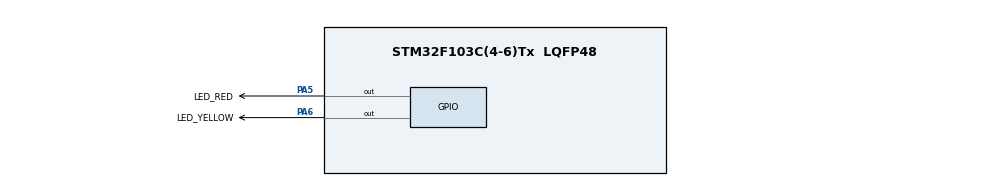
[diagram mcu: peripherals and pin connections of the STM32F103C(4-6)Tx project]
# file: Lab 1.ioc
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Mcu.Family=STM32F1
Mcu.Name=STM32F103C(4-6)Tx
Mcu.Package=LQFP48
NVIC.PriorityGroup=NVIC_PRIORITYGROUP_4
PA5.GPIO_Label=LED_RED
PA5.Signal=GPIO_Output
PA6.GPIO_Label=LED_YELLOW
PA6.Signal=GPIO_Output
ProjectManager.HeapSize=0x200
ProjectManager.StackSize=0x400
ProjectManager.TargetToolchain=STM32CubeIDE
RCC.APB1Freq_Value=8000000
RCC.APB2Freq_Value=8000000
VP_SYS_VS_ND.Mode=No_Debug
board=custom

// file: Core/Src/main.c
/* USER CODE BEGIN Header */
/**
 ******************************************************************************
 * @file           : main.c
 * @brief          : Main program body
 ******************************************************************************
 * @attention
 *
 * Copyright (c) 2025 STMicroelectronics.
 * All rights reserved.
 *
 * This software is licensed under terms that can be found in the LICENSE file
 * in the root directory of this software component.
 * If no LICENSE file comes with this software, it is provided AS-IS.
 *
 ******************************************************************************
 */
/* USER CODE END Header */
#include "main.h"

/* USER CODE BEGIN PV */

int LED_Pins[12] = {
    LED1_Pin, LED2_Pin, LED3_Pin, LED4_Pin,
    LED5_Pin, LED6_Pin, LED7_Pin, LED8_Pin,
    LED9_Pin, LED10_Pin, LED11_Pin, LED12_Pin
};

/* USER CODE END PV */

void SystemClock_Config(void);
static void MX_GPIO_Init(void);

/* USER CODE BEGIN 0 */

void setAllClock()
{
	for (int i = 0; i < 12; i++)
	{
		HAL_GPIO_WritePin(GPIOA, LED_Pins[i], GPIO_PIN_SET);
	}
}

void clearAllClock()
{
	for (int i = 0; i < 12; i++)
	{
		HAL_GPIO_WritePin(GPIOA, LED_Pins[i], GPIO_PIN_RESET);
	}
}

void setNumberOnClock(int num)
{
    HAL_GPIO_WritePin(GPIOA, LED_Pins[num], GPIO_PIN_SET);
}

void clearNumberOnClock(int num)
{
    HAL_GPIO_WritePin(GPIOA, LED_Pins[num], GPIO_PIN_RESET);
}

/* USER CODE END 0 */

int main(void)
{

  /* MCU Configuration--------------------------------------------------------*/

  /* Reset of all peripherals, Initializes the Flash interface and the Systick. */
  HAL_Init();

  /* Configure the system clock */
  SystemClock_Config();

  /* Initialize all configured peripherals */
  MX_GPIO_Init();

  /* Infinite loop */
  /* USER CODE BEGIN WHILE */

    int current_led = 0;
    setAllClock();
    HAL_Delay(250);
    while(1)
    {
    /* USER CODE END WHILE */

    /* USER CODE BEGIN 3 */
    	if(current_led < 12)
		{
			clearNumberOnClock(current_led);
			current_led++;
		}
    	else
    	{
    		setAllClock();
			current_led = 0;
		}

		HAL_Delay(250);
    }
  /* USER CODE END 3 */
}

void SystemClock_Config(void)
{
  RCC_OscInitTypeDef RCC_OscInitStruct = {0};
  RCC_ClkInitTypeDef RCC_ClkInitStruct = {0};

  /** Initializes the RCC Oscillators according to the specified parameters
  * in the RCC_OscInitTypeDef structure.
  */
  RCC_OscInitStruct.OscillatorType = RCC_OSCILLATORTYPE_HSI;
  RCC_OscInitStruct.HSIState = RCC_HSI_ON;
  RCC_OscInitStruct.HSICalibrationValue = RCC_HSICALIBRATION_DEFAULT;
  RCC_OscInitStruct.PLL.PLLState = RCC_PLL_NONE;
  if (HAL_RCC_OscConfig(&RCC_OscInitStruct) != HAL_OK)
  {
    Error_Handler();
  }

  /** Initializes the CPU, AHB and APB buses clocks
  */
  RCC_ClkInitStruct.ClockType = RCC_CLOCKTYPE_HCLK|RCC_CLOCKTYPE_SYSCLK
                              |RCC_CLOCKTYPE_PCLK1|RCC_CLOCKTYPE_PCLK2;
  RCC_ClkInitStruct.SYSCLKSource = RCC_SYSCLKSOURCE_HSI;
  RCC_ClkInitStruct.AHBCLKDivider = RCC_SYSCLK_DIV1;
  RCC_ClkInitStruct.APB1CLKDivider = RCC_HCLK_DIV1;
  RCC_ClkInitStruct.APB2CLKDivider = RCC_HCLK_DIV1;

  if (HAL_RCC_ClockConfig(&RCC_ClkInitStruct, FLASH_LATENCY_0) != HAL_OK)
  {
    Error_Handler();
  }
}

static void MX_GPIO_Init(void)
{
  GPIO_InitTypeDef GPIO_InitStruct = {0};

  /* GPIO Ports Clock Enable */
  __HAL_RCC_GPIOA_CLK_ENABLE();

  /*Configure GPIO pin Output Level */
  HAL_GPIO_WritePin(GPIOA, LED1_Pin|LED2_Pin|LED3_Pin|LED4_Pin
                          |LED5_Pin|LED6_Pin|LED7_Pin|LED8_Pin
                          |LED9_Pin|LED10_Pin|LED11_Pin|LED12_Pin, GPIO_PIN_RESET);

  /*Configure GPIO pins : LED1_Pin LED2_Pin LED3_Pin LED4_Pin
                           LED5_Pin LED6_Pin LED7_Pin LED8_Pin
                           LED9_Pin LED10_Pin LED11_Pin LED12_Pin */
  GPIO_InitStruct.Pin = LED1_Pin|LED2_Pin|LED3_Pin|LED4_Pin
                          |LED5_Pin|LED6_Pin|LED7_Pin|LED8_Pin
                          |LED9_Pin|LED10_Pin|LED11_Pin|LED12_Pin;
  GPIO_InitStruct.Mode = GPIO_MODE_OUTPUT_PP;
  GPIO_InitStruct.Pull = GPIO_NOPULL;
  GPIO_InitStruct.Speed = GPIO_SPEED_FREQ_LOW;
  HAL_GPIO_Init(GPIOA, &GPIO_InitStruct);

}

void Error_Handler(void)
{
  /* USER CODE BEGIN Error_Handler_Debug */
    /* User can add his own implementation to report the HAL error return state
     */
    __disable_irq();
    while(1)
    {
    }
  /* USER CODE END Error_Handler_Debug */
}
#ifdef USE_FULL_ASSERT
/**
  * @brief  Reports the name of the source file and the source line number
  *         where the assert_param error has occurred.
  * @param  file: pointer to the source file name
  * @param  line: assert_param error line source number
  * @retval None
  */
void assert_failed(uint8_t *file, uint32_t line)
{
  /* USER CODE BEGIN 6 */
    /* User can add his own implementation to report the file name and line
       number, ex: printf("Wrong parameters value: file %s on line %d\r\n",
       file, line) */
  /* USER CODE END 6 */
}
#endif /* USE_FULL_ASSERT */
